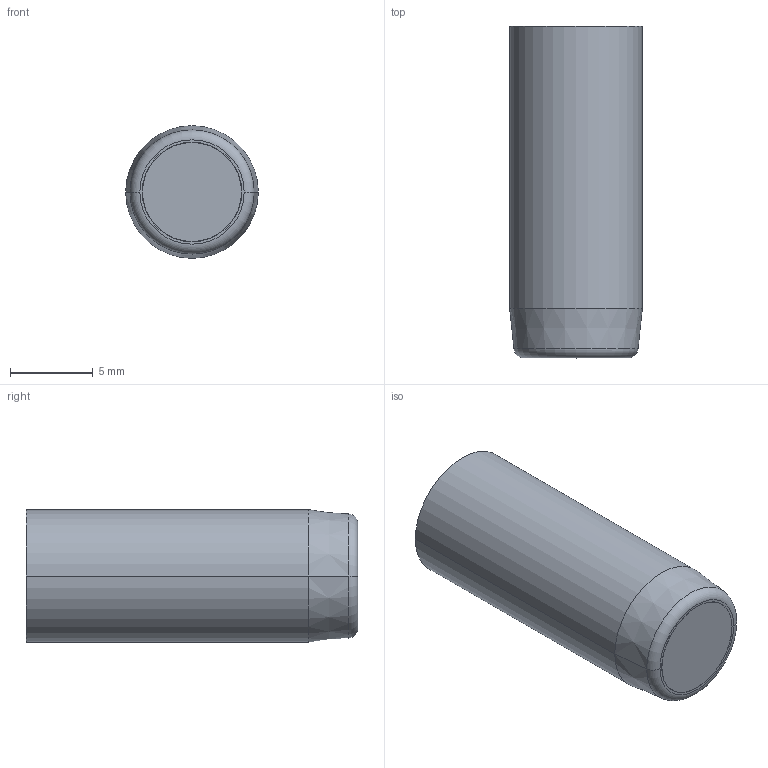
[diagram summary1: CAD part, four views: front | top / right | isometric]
STEP (ISO 10303-21) file: header records copied from the file, then geometry measured from it (millimetres).
FILE_DESCRIPTION (( 'STEP AP214' ), '1' );
FILE_NAME ('FA0847SF.STEP', '2013-06-28T07:38:54', ( '' ), ( '' ), 'SwSTEP 2.0', 'SolidWorks 2011', '' );
FILE_SCHEMA (( 'AUTOMOTIVE_DESIGN' ));
Length unit declared in the file: millimetre
Products named in the file (6): FA 084700-1; FA 084700-2 comprimido; 9FA 084712; FA0847SF; IA 4717SF; FA 084700-3
Assembly tree (5 placements, depth 2):
  FA0847SF
    9FA 084712
    FA 084700-3
    IA 4717SF
    FA 084700-1
    FA 084700-2 comprimido
Bounding box: 8 x 20 x 8 mm (x, y, z)
Volume: 846.9 mm3; surface area: 1512.7 mm2
Topology: 5 solids, 5 shells, 306 faces, 770 edges, 500 vertices
Faces by surface type: plane 139, cylinder 127, cone 24, torus 12, sphere 2, bspline 2
Entity records: 10886 total; most frequent: CARTESIAN_POINT 3040, DIRECTION 1662, ORIENTED_EDGE 1536, EDGE_CURVE 768, AXIS2_PLACEMENT_3D 618, VERTEX_POINT 500, VECTOR 426, LINE 426
One B-rep face of a CAD part: STEP entity #747.
In plain terms, the planar face has unit normal (0, -1, 0).
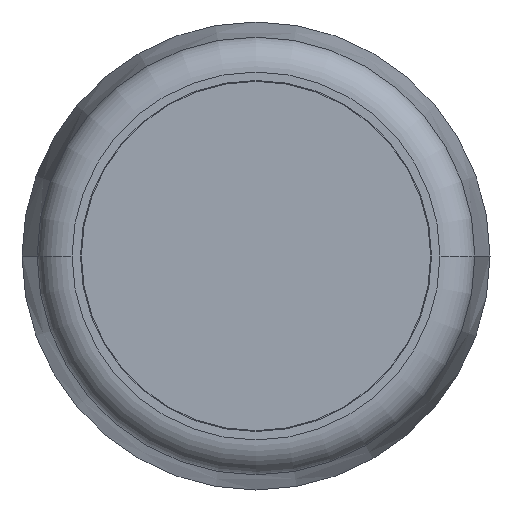
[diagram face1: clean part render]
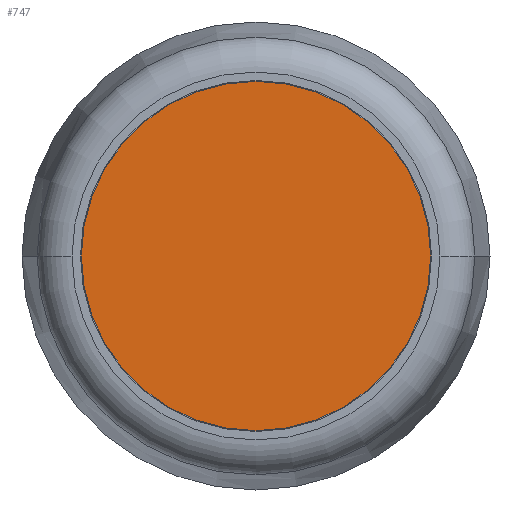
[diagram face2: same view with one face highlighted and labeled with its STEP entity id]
Its self-contained STEP definition (entity closure, numbers rounded to 3 decimals):
#747 = ADVANCED_FACE ( 'NONE', ( #3570 ), #3569, .F. ) ;
#938 = AXIS2_PLACEMENT_3D ( 'NONE', #3560, #3561, #3583 ) ;
#2602 = EDGE_CURVE ( 'NONE', #9580, #9602, #5132, .T. ) ;
#2618 = EDGE_CURVE ( 'NONE', #9602, #9580, #5120, .T. ) ;
#3560 = CARTESIAN_POINT ( 'NONE',  ( -3.068, 0.2, -10. ) ) ;
#3561 = DIRECTION ( 'NONE',  ( 0., 1., 0. ) ) ;
#3569 = PLANE ( 'NONE',  #938 ) ;
#3570 = FACE_OUTER_BOUND ( 'NONE', #10129, .T. ) ;
#3583 = DIRECTION ( 'NONE',  ( 0., 0., 1. ) ) ;
#5120 = CIRCLE ( 'NONE', #5153, 3. ) ;
#5124 = AXIS2_PLACEMENT_3D ( 'NONE', #6899, #6910, #6908 ) ;
#5132 = CIRCLE ( 'NONE', #5124, 3. ) ;
#5153 = AXIS2_PLACEMENT_3D ( 'NONE', #7008, #6991, #6992 ) ;
#6899 = CARTESIAN_POINT ( 'NONE',  ( 0., 0.2, 0. ) ) ;
#6908 = DIRECTION ( 'NONE',  ( 0., 0., 1. ) ) ;
#6910 = DIRECTION ( 'NONE',  ( 0., 1., 0. ) ) ;
#6991 = DIRECTION ( 'NONE',  ( 0., 1., 0. ) ) ;
#6992 = DIRECTION ( 'NONE',  ( 0., 0., 1. ) ) ;
#7008 = CARTESIAN_POINT ( 'NONE',  ( 0., 0.2, 0. ) ) ;
#7947 = CARTESIAN_POINT ( 'NONE',  ( 0., 0.2, 3. ) ) ;
#8043 = CARTESIAN_POINT ( 'NONE',  ( 0., 0.2, -3. ) ) ;
#9423 = ORIENTED_EDGE ( 'NONE', *, *, #2618, .F. ) ;
#9479 = ORIENTED_EDGE ( 'NONE', *, *, #2602, .F. ) ;
#9580 = VERTEX_POINT ( 'NONE', #7947 ) ;
#9602 = VERTEX_POINT ( 'NONE', #8043 ) ;
#10129 = EDGE_LOOP ( 'NONE', ( #9479, #9423 ) ) ;
